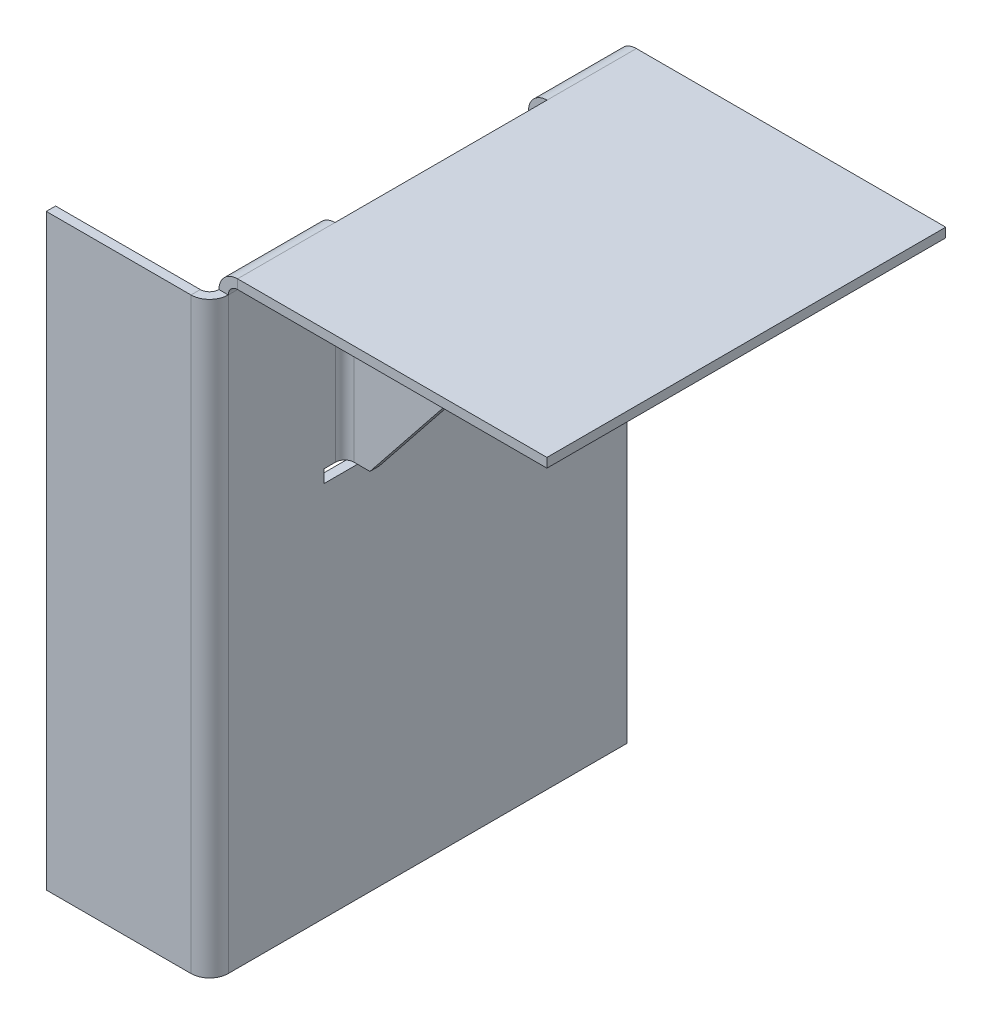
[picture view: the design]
ISO-10303-21;
HEADER;
FILE_DESCRIPTION(('STEP AP214'),'2;1');
FILE_NAME('part.step','',(''),(''),'','','');
FILE_SCHEMA(('AUTOMOTIVE_DESIGN { 1 0 10303 214 1 1 1 1 }'));
ENDSEC;
DATA;
#1=APPLICATION_CONTEXT('core data for automotive mechanical design processes');
#2=APPLICATION_PROTOCOL_DEFINITION('international standard','automotive_design',2000,#1);
#3=PRODUCT_CONTEXT('',#1,'mechanical');
#4=PRODUCT('Part','Part','',(#3));
#5=PRODUCT_RELATED_PRODUCT_CATEGORY('part','',(#4));
#6=PRODUCT_DEFINITION_FORMATION('','',#4);
#7=PRODUCT_DEFINITION_CONTEXT('part definition',#1,'design');
#8=PRODUCT_DEFINITION('design','',#6,#7);
#9=PRODUCT_DEFINITION_SHAPE('','',#8);
#10=(LENGTH_UNIT() NAMED_UNIT(*) SI_UNIT(.MILLI.,.METRE.));
#11=(NAMED_UNIT(*) PLANE_ANGLE_UNIT() SI_UNIT($,.RADIAN.));
#12=(NAMED_UNIT(*) SI_UNIT($,.STERADIAN.) SOLID_ANGLE_UNIT());
#13=UNCERTAINTY_MEASURE_WITH_UNIT(LENGTH_MEASURE(1.E-05),#10,'distance_accuracy_value','');
#14=(GEOMETRIC_REPRESENTATION_CONTEXT(3) GLOBAL_UNCERTAINTY_ASSIGNED_CONTEXT((#13)) GLOBAL_UNIT_ASSIGNED_CONTEXT((#10,
#11,#12)) REPRESENTATION_CONTEXT('',''));
#15=CARTESIAN_POINT('',(0.,0.,0.));
#16=DIRECTION('',(0.,0.,1.));
#17=DIRECTION('',(1.,0.,0.));
#18=AXIS2_PLACEMENT_3D('',#15,#16,#17);
#19=CARTESIAN_POINT('',(36.7177895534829,62.411644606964,-12.5039962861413));
#20=DIRECTION('',(0.,-1.,0.));
#21=DIRECTION('',(1.,0.,0.));
#22=AXIS2_PLACEMENT_3D('',#19,#20,#21);
#23=PLANE('',#22);
#24=DIRECTION('',(-1.,0.,0.));
#25=VECTOR('',#24,1.);
#26=CARTESIAN_POINT('',(36.717789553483,62.411644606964,-14.5039962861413));
#27=LINE('',#26,#25);
#28=CARTESIAN_POINT('',(36.717789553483,62.411644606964,-14.5039962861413));
#29=VERTEX_POINT('',#28);
#30=CARTESIAN_POINT('',(34.0135990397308,62.411644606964,-14.5039962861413));
#31=VERTEX_POINT('',#30);
#32=EDGE_CURVE('E74',#29,#31,#27,.T.);
#33=ORIENTED_EDGE('',*,*,#32,.T.);
#34=DIRECTION('',(0.,0.,-1.));
#35=VECTOR('',#34,1.);
#36=CARTESIAN_POINT('',(34.0135990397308,62.411644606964,-13.5039962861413));
#37=LINE('',#36,#35);
#38=CARTESIAN_POINT('',(34.0135990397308,62.411644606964,-13.5039962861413));
#39=VERTEX_POINT('',#38);
#40=EDGE_CURVE('E78',#39,#31,#37,.T.);
#41=ORIENTED_EDGE('',*,*,#40,.F.);
#42=DIRECTION('',(1.,0.,0.));
#43=VECTOR('',#42,1.);
#44=CARTESIAN_POINT('',(3.67105116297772,62.411644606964,-13.5039962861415));
#45=LINE('',#44,#43);
#46=CARTESIAN_POINT('',(36.717789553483,62.411644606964,-13.5039962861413));
#47=VERTEX_POINT('',#46);
#48=EDGE_CURVE('E305',#39,#47,#45,.T.);
#49=ORIENTED_EDGE('',*,*,#48,.T.);
#50=DIRECTION('',(0.,0.,-1.));
#51=VECTOR('',#50,1.);
#52=CARTESIAN_POINT('',(36.7177895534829,62.411644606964,-12.5039962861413));
#53=LINE('',#52,#51);
#54=EDGE_CURVE('E301',#47,#29,#53,.T.);
#55=ORIENTED_EDGE('',*,*,#54,.T.);
#56=EDGE_LOOP('',(#33,#41,#49,#55));
#57=FACE_BOUND('',#56,.T.);
#58=ADVANCED_FACE('F57',(#57),#23,.F.);
#59=CARTESIAN_POINT('',(18.5312419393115,41.7710744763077,-16.5624605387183));
#60=DIRECTION('',(0.,1.,0.));
#61=DIRECTION('',(0.,0.,1.));
#62=AXIS2_PLACEMENT_3D('',#59,#60,#61);
#63=PLANE('',#62);
#64=DIRECTION('',(0.,0.,-1.));
#65=VECTOR('',#64,1.);
#66=CARTESIAN_POINT('',(16.5312419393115,41.7710744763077,-16.5624605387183));
#67=LINE('',#66,#65);
#68=CARTESIAN_POINT('',(16.5312419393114,41.7710744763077,-11.2878468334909));
#69=VERTEX_POINT('',#68);
#70=CARTESIAN_POINT('',(16.5312419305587,41.7710744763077,-12.5039962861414));
#71=VERTEX_POINT('',#70);
#72=EDGE_CURVE('E61',#69,#71,#67,.T.);
#73=ORIENTED_EDGE('',*,*,#72,.T.);
#74=DIRECTION('',(1.,0.,0.));
#75=VECTOR('',#74,1.);
#76=CARTESIAN_POINT('',(18.5312419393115,41.7710744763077,-12.5039962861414));
#77=LINE('',#76,#75);
#78=CARTESIAN_POINT('',(17.5312419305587,41.7710744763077,-12.5039962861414));
#79=VERTEX_POINT('',#78);
#80=EDGE_CURVE('E524',#71,#79,#77,.T.);
#81=ORIENTED_EDGE('',*,*,#80,.T.);
#82=DIRECTION('',(0.,0.,1.));
#83=VECTOR('',#82,1.);
#84=CARTESIAN_POINT('',(17.5312419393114,41.7710744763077,0.));
#85=LINE('',#84,#83);
#86=CARTESIAN_POINT('',(17.5312419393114,41.7710744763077,-11.2878468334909));
#87=VERTEX_POINT('',#86);
#88=EDGE_CURVE('E387',#79,#87,#85,.T.);
#89=ORIENTED_EDGE('',*,*,#88,.T.);
#90=DIRECTION('',(-1.,0.,0.));
#91=VECTOR('',#90,1.);
#92=CARTESIAN_POINT('',(18.5312419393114,41.7710744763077,-11.2878468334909));
#93=LINE('',#92,#91);
#94=EDGE_CURVE('E362',#87,#69,#93,.T.);
#95=ORIENTED_EDGE('',*,*,#94,.T.);
#96=EDGE_LOOP('',(#73,#81,#89,#95));
#97=FACE_BOUND('',#96,.T.);
#98=ADVANCED_FACE('F535',(#97),#63,.F.);
#99=CARTESIAN_POINT('',(18.5312419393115,62.411644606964,-33.0467383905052));
#100=DIRECTION('',(0.,-1.,0.));
#101=DIRECTION('',(0.,0.,-1.));
#102=AXIS2_PLACEMENT_3D('',#99,#100,#101);
#103=PLANE('',#102);
#104=DIRECTION('',(0.,0.,-1.));
#105=VECTOR('',#104,1.);
#106=CARTESIAN_POINT('',(17.5312419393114,62.411644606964,0.));
#107=LINE('',#106,#105);
#108=CARTESIAN_POINT('',(17.5312419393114,62.411644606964,-11.4539814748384));
#109=VERTEX_POINT('',#108);
#110=CARTESIAN_POINT('',(17.5312419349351,62.411644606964,-12.5039962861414));
#111=VERTEX_POINT('',#110);
#112=EDGE_CURVE('E425',#109,#111,#107,.T.);
#113=ORIENTED_EDGE('',*,*,#112,.T.);
#114=DIRECTION('',(-1.,0.,0.));
#115=VECTOR('',#114,1.);
#116=CARTESIAN_POINT('',(18.5312419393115,62.411644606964,-12.5039962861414));
#117=LINE('',#116,#115);
#118=CARTESIAN_POINT('',(16.5312419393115,62.411644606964,-12.5039962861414));
#119=VERTEX_POINT('',#118);
#120=EDGE_CURVE('E13',#111,#119,#117,.T.);
#121=ORIENTED_EDGE('',*,*,#120,.T.);
#122=DIRECTION('',(0.,0.,1.));
#123=VECTOR('',#122,1.);
#124=CARTESIAN_POINT('',(16.5312419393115,62.411644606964,-33.0467383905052));
#125=LINE('',#124,#123);
#126=CARTESIAN_POINT('',(16.5312419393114,62.411644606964,-11.4539814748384));
#127=VERTEX_POINT('',#126);
#128=EDGE_CURVE('E336',#119,#127,#125,.T.);
#129=ORIENTED_EDGE('',*,*,#128,.T.);
#130=DIRECTION('',(-1.,0.,0.));
#131=VECTOR('',#130,1.);
#132=CARTESIAN_POINT('',(18.5312419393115,62.411644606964,-11.4539814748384));
#133=LINE('',#132,#131);
#134=EDGE_CURVE('E347',#109,#127,#133,.T.);
#135=ORIENTED_EDGE('',*,*,#134,.F.);
#136=EDGE_LOOP('',(#113,#121,#129,#135));
#137=FACE_BOUND('',#136,.T.);
#138=ADVANCED_FACE('F59',(#137),#103,.F.);
#139=CARTESIAN_POINT('',(16.5312419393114,0.,0.));
#140=DIRECTION('',(1.,0.,0.));
#141=DIRECTION('',(0.,0.,-1.));
#142=AXIS2_PLACEMENT_3D('',#139,#140,#141);
#143=PLANE('',#142);
#144=ORIENTED_EDGE('',*,*,#128,.F.);
#145=DIRECTION('',(0.,-1.,0.));
#146=VECTOR('',#145,1.);
#147=CARTESIAN_POINT('',(16.5312419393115,0.,-12.5039962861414));
#148=LINE('',#147,#146);
#149=EDGE_CURVE('E66',#119,#71,#148,.T.);
#150=ORIENTED_EDGE('',*,*,#149,.T.);
#151=ORIENTED_EDGE('',*,*,#72,.F.);
#152=DIRECTION('',(0.,1.,0.));
#153=VECTOR('',#152,1.);
#154=CARTESIAN_POINT('',(16.5312419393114,41.7710744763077,-11.2878468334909));
#155=LINE('',#154,#153);
#156=CARTESIAN_POINT('',(16.5312419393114,40.4026864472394,-11.2878468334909));
#157=VERTEX_POINT('',#156);
#158=EDGE_CURVE('E359',#157,#69,#155,.T.);
#159=ORIENTED_EDGE('',*,*,#158,.F.);
#160=DIRECTION('',(0.,0.,1.));
#161=VECTOR('',#160,1.);
#162=CARTESIAN_POINT('',(16.5312419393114,40.4026864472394,-11.2878468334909));
#163=LINE('',#162,#161);
#164=CARTESIAN_POINT('',(16.5312419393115,40.4026864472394,-16.9317383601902));
#165=VERTEX_POINT('',#164);
#166=EDGE_CURVE('E356',#165,#157,#163,.T.);
#167=ORIENTED_EDGE('',*,*,#166,.F.);
#168=DIRECTION('',(0.,-0.781388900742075,0.62404437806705));
#169=VECTOR('',#168,1.);
#170=CARTESIAN_POINT('',(16.5312419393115,40.4026864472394,-16.9317383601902));
#171=LINE('',#170,#169);
#172=CARTESIAN_POINT('',(16.5312419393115,62.0423667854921,-34.2139404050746));
#173=VERTEX_POINT('',#172);
#174=EDGE_CURVE('E353',#173,#165,#171,.T.);
#175=ORIENTED_EDGE('',*,*,#174,.F.);
#176=DIRECTION('',(0.,-1.,0.));
#177=VECTOR('',#176,1.);
#178=CARTESIAN_POINT('',(16.5312419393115,62.0423667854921,-34.2139404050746));
#179=LINE('',#178,#177);
#180=CARTESIAN_POINT('',(16.5312419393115,63.0741376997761,-34.2139404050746));
#181=VERTEX_POINT('',#180);
#182=EDGE_CURVE('E350',#181,#173,#179,.T.);
#183=ORIENTED_EDGE('',*,*,#182,.F.);
#184=DIRECTION('',(0.,0.,-1.));
#185=VECTOR('',#184,1.);
#186=CARTESIAN_POINT('',(16.5312419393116,63.0741376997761,-43.8));
#187=LINE('',#186,#185);
#188=CARTESIAN_POINT('',(16.5312419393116,63.0741376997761,-43.8));
#189=VERTEX_POINT('',#188);
#190=EDGE_CURVE('E447',#181,#189,#187,.T.);
#191=ORIENTED_EDGE('',*,*,#190,.T.);
#192=DIRECTION('',(0.,-1.,0.));
#193=VECTOR('',#192,1.);
#194=CARTESIAN_POINT('',(16.5312419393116,0.,-43.8));
#195=LINE('',#194,#193);
#196=CARTESIAN_POINT('',(16.5312419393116,0.,-43.8));
#197=VERTEX_POINT('',#196);
#198=EDGE_CURVE('E462',#189,#197,#195,.T.);
#199=ORIENTED_EDGE('',*,*,#198,.T.);
#200=DIRECTION('',(0.,0.,1.));
#201=VECTOR('',#200,1.);
#202=CARTESIAN_POINT('',(16.5312419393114,0.,0.));
#203=LINE('',#202,#201);
#204=CARTESIAN_POINT('',(16.5312419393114,0.,-0.999999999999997));
#205=VERTEX_POINT('',#204);
#206=EDGE_CURVE('E465',#197,#205,#203,.T.);
#207=ORIENTED_EDGE('',*,*,#206,.T.);
#208=DIRECTION('',(0.,-1.,0.));
#209=VECTOR('',#208,1.);
#210=CARTESIAN_POINT('',(16.5312419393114,63.0741376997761,-0.999999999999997));
#211=LINE('',#210,#209);
#212=CARTESIAN_POINT('',(16.5312419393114,63.0741376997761,-0.999999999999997));
#213=VERTEX_POINT('',#212);
#214=EDGE_CURVE('E438',#213,#205,#211,.T.);
#215=ORIENTED_EDGE('',*,*,#214,.F.);
#216=CARTESIAN_POINT('',(16.5312419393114,63.0741376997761,-11.4539814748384));
#217=VERTEX_POINT('',#216);
#218=EDGE_CURVE('E459',#213,#217,#187,.T.);
#219=ORIENTED_EDGE('',*,*,#218,.T.);
#220=DIRECTION('',(0.,1.,0.));
#221=VECTOR('',#220,1.);
#222=CARTESIAN_POINT('',(16.5312419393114,62.411644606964,-11.4539814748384));
#223=LINE('',#222,#221);
#224=EDGE_CURVE('E348',#127,#217,#223,.T.);
#225=ORIENTED_EDGE('',*,*,#224,.F.);
#226=EDGE_LOOP('',(#144,#150,#151,#159,#167,#175,#183,#191,#199,#207,#215,#219,#225));
#227=FACE_BOUND('',#226,.T.);
#228=ADVANCED_FACE('F559',(#227),#143,.F.);
#229=CARTESIAN_POINT('',(18.5312419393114,63.0741376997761,-0.99999999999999));
#230=DIRECTION('',(0.,0.,1.));
#231=DIRECTION('',(0.,1.,0.));
#232=AXIS2_PLACEMENT_3D('',#229,#230,#231);
#233=CYLINDRICAL_SURFACE('',#232,2.);
#234=CARTESIAN_POINT('',(18.5312419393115,63.0741376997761,-34.2139404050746));
#235=DIRECTION('',(0.,0.,-1.));
#236=DIRECTION('',(-1.,0.,0.));
#237=AXIS2_PLACEMENT_3D('',#234,#235,#236);
#238=CIRCLE('',#237,2.);
#239=CARTESIAN_POINT('',(18.5312419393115,65.0741376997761,-34.2139404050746));
#240=VERTEX_POINT('',#239);
#241=EDGE_CURVE('E379',#240,#181,#238,.F.);
#242=ORIENTED_EDGE('',*,*,#241,.F.);
#243=DIRECTION('',(0.,0.,1.));
#244=VECTOR('',#243,1.);
#245=CARTESIAN_POINT('',(18.5312419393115,65.0741376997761,-43.7999999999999));
#246=LINE('',#245,#244);
#247=CARTESIAN_POINT('',(18.5312419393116,65.0741376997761,-43.8));
#248=VERTEX_POINT('',#247);
#249=EDGE_CURVE('E413',#240,#248,#246,.F.);
#250=ORIENTED_EDGE('',*,*,#249,.T.);
#251=CARTESIAN_POINT('',(18.5312419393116,63.0741376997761,-43.8));
#252=DIRECTION('',(0.,0.,1.));
#253=DIRECTION('',(1.,0.,0.));
#254=AXIS2_PLACEMENT_3D('',#251,#252,#253);
#255=CIRCLE('',#254,2.);
#256=EDGE_CURVE('E426',#189,#248,#255,.F.);
#257=ORIENTED_EDGE('',*,*,#256,.F.);
#258=ORIENTED_EDGE('',*,*,#190,.F.);
#259=EDGE_LOOP('',(#242,#250,#257,#258));
#260=FACE_BOUND('',#259,.T.);
#261=ADVANCED_FACE('F807',(#260),#233,.T.);
#262=CARTESIAN_POINT('',(18.5312419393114,63.0741376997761,-0.99999999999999));
#263=DIRECTION('',(0.,0.,1.));
#264=DIRECTION('',(0.,1.,0.));
#265=AXIS2_PLACEMENT_3D('',#262,#263,#264);
#266=CYLINDRICAL_SURFACE('',#265,1.);
#267=DIRECTION('',(0.,0.,1.));
#268=VECTOR('',#267,1.);
#269=CARTESIAN_POINT('',(18.5312419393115,64.0741376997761,-43.7999999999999));
#270=LINE('',#269,#268);
#271=CARTESIAN_POINT('',(18.5312419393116,64.0741376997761,-43.8));
#272=VERTEX_POINT('',#271);
#273=CARTESIAN_POINT('',(18.5312419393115,64.0741376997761,-34.2139404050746));
#274=VERTEX_POINT('',#273);
#275=EDGE_CURVE('E417',#272,#274,#270,.T.);
#276=ORIENTED_EDGE('',*,*,#275,.T.);
#277=CARTESIAN_POINT('',(18.5312419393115,63.0741376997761,-34.2139404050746));
#278=DIRECTION('',(0.,0.,-1.));
#279=DIRECTION('',(-1.,0.,0.));
#280=AXIS2_PLACEMENT_3D('',#277,#278,#279);
#281=CIRCLE('',#280,1.);
#282=CARTESIAN_POINT('',(17.5312419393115,63.0741376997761,-34.2139404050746));
#283=VERTEX_POINT('',#282);
#284=EDGE_CURVE('E519',#274,#283,#281,.F.);
#285=ORIENTED_EDGE('',*,*,#284,.T.);
#286=DIRECTION('',(0.,0.,-1.));
#287=VECTOR('',#286,1.);
#288=CARTESIAN_POINT('',(17.5312419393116,63.0741376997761,-43.8));
#289=LINE('',#288,#287);
#290=CARTESIAN_POINT('',(17.5312419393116,63.0741376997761,-43.8));
#291=VERTEX_POINT('',#290);
#292=EDGE_CURVE('E452',#283,#291,#289,.T.);
#293=ORIENTED_EDGE('',*,*,#292,.T.);
#294=CARTESIAN_POINT('',(18.5312419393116,63.0741376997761,-43.8));
#295=DIRECTION('',(0.,0.,1.));
#296=DIRECTION('',(1.,0.,0.));
#297=AXIS2_PLACEMENT_3D('',#294,#295,#296);
#298=CIRCLE('',#297,1.);
#299=EDGE_CURVE('E433',#291,#272,#298,.F.);
#300=ORIENTED_EDGE('',*,*,#299,.T.);
#301=EDGE_LOOP('',(#276,#285,#293,#300));
#302=FACE_BOUND('',#301,.T.);
#303=ADVANCED_FACE('F865',(#302),#266,.F.);
#304=CARTESIAN_POINT('',(0.,0.,1.));
#305=DIRECTION('',(0.,1.,0.));
#306=DIRECTION('',(0.,0.,1.));
#307=AXIS2_PLACEMENT_3D('',#304,#305,#306);
#308=PLANE('',#307);
#309=DIRECTION('',(0.,0.,1.));
#310=VECTOR('',#309,1.);
#311=CARTESIAN_POINT('',(15.5312419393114,0.,0.));
#312=LINE('',#311,#310);
#313=CARTESIAN_POINT('',(15.5312419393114,0.,0.));
#314=VERTEX_POINT('',#313);
#315=CARTESIAN_POINT('',(15.5312419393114,0.,1.));
#316=VERTEX_POINT('',#315);
#317=EDGE_CURVE('E479',#314,#316,#312,.T.);
#318=ORIENTED_EDGE('',*,*,#317,.T.);
#319=DIRECTION('',(1.,0.,0.));
#320=VECTOR('',#319,1.);
#321=CARTESIAN_POINT('',(0.,0.,1.));
#322=LINE('',#321,#320);
#323=CARTESIAN_POINT('',(0.,0.,1.));
#324=VERTEX_POINT('',#323);
#325=EDGE_CURVE('E499',#324,#316,#322,.T.);
#326=ORIENTED_EDGE('',*,*,#325,.F.);
#327=DIRECTION('',(0.,0.,-1.));
#328=VECTOR('',#327,1.);
#329=CARTESIAN_POINT('',(0.,0.,1.));
#330=LINE('',#329,#328);
#331=CARTESIAN_POINT('',(0.,0.,0.));
#332=VERTEX_POINT('',#331);
#333=EDGE_CURVE('E513',#324,#332,#330,.T.);
#334=ORIENTED_EDGE('',*,*,#333,.T.);
#335=DIRECTION('',(1.,0.,0.));
#336=VECTOR('',#335,1.);
#337=CARTESIAN_POINT('',(0.,0.,0.));
#338=LINE('',#337,#336);
#339=EDGE_CURVE('E507',#332,#314,#338,.T.);
#340=ORIENTED_EDGE('',*,*,#339,.T.);
#341=EDGE_LOOP('',(#318,#326,#334,#340));
#342=FACE_BOUND('',#341,.T.);
#343=ADVANCED_FACE('F605',(#342),#308,.F.);
#344=CARTESIAN_POINT('',(0.,63.0741376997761,1.));
#345=DIRECTION('',(0.,-1.,0.));
#346=DIRECTION('',(0.,0.,-1.));
#347=AXIS2_PLACEMENT_3D('',#344,#345,#346);
#348=PLANE('',#347);
#349=DIRECTION('',(0.,0.,1.));
#350=VECTOR('',#349,1.);
#351=CARTESIAN_POINT('',(15.5312419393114,63.0741376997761,0.));
#352=LINE('',#351,#350);
#353=CARTESIAN_POINT('',(15.5312419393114,63.0741376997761,0.));
#354=VERTEX_POINT('',#353);
#355=CARTESIAN_POINT('',(15.5312419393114,63.0741376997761,1.));
#356=VERTEX_POINT('',#355);
#357=EDGE_CURVE('E490',#354,#356,#352,.T.);
#358=ORIENTED_EDGE('',*,*,#357,.F.);
#359=DIRECTION('',(-1.,0.,0.));
#360=VECTOR('',#359,1.);
#361=CARTESIAN_POINT('',(0.,63.0741376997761,0.));
#362=LINE('',#361,#360);
#363=CARTESIAN_POINT('',(0.,63.0741376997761,0.));
#364=VERTEX_POINT('',#363);
#365=EDGE_CURVE('E500',#354,#364,#362,.T.);
#366=ORIENTED_EDGE('',*,*,#365,.T.);
#367=DIRECTION('',(0.,0.,-1.));
#368=VECTOR('',#367,1.);
#369=CARTESIAN_POINT('',(0.,63.0741376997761,1.));
#370=LINE('',#369,#368);
#371=CARTESIAN_POINT('',(0.,63.0741376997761,1.));
#372=VERTEX_POINT('',#371);
#373=EDGE_CURVE('E504',#372,#364,#370,.T.);
#374=ORIENTED_EDGE('',*,*,#373,.F.);
#375=DIRECTION('',(-1.,0.,0.));
#376=VECTOR('',#375,1.);
#377=CARTESIAN_POINT('',(0.,63.0741376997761,1.));
#378=LINE('',#377,#376);
#379=EDGE_CURVE('E502',#356,#372,#378,.T.);
#380=ORIENTED_EDGE('',*,*,#379,.F.);
#381=EDGE_LOOP('',(#358,#366,#374,#380));
#382=FACE_BOUND('',#381,.T.);
#383=ADVANCED_FACE('F619',(#382),#348,.F.);
#384=CARTESIAN_POINT('',(0.,63.0741376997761,1.));
#385=DIRECTION('',(0.,0.,-1.));
#386=DIRECTION('',(-1.,0.,0.));
#387=AXIS2_PLACEMENT_3D('',#384,#385,#386);
#388=PLANE('',#387);
#389=DIRECTION('',(0.,-1.,0.));
#390=VECTOR('',#389,1.);
#391=CARTESIAN_POINT('',(15.5312419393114,0.,1.));
#392=LINE('',#391,#390);
#393=EDGE_CURVE('E473',#316,#356,#392,.F.);
#394=ORIENTED_EDGE('',*,*,#393,.T.);
#395=ORIENTED_EDGE('',*,*,#379,.T.);
#396=DIRECTION('',(0.,-1.,0.));
#397=VECTOR('',#396,1.);
#398=CARTESIAN_POINT('',(0.,0.,1.));
#399=LINE('',#398,#397);
#400=EDGE_CURVE('E496',#372,#324,#399,.T.);
#401=ORIENTED_EDGE('',*,*,#400,.T.);
#402=ORIENTED_EDGE('',*,*,#325,.T.);
#403=EDGE_LOOP('',(#394,#395,#401,#402));
#404=FACE_BOUND('',#403,.T.);
#405=ADVANCED_FACE('F616',(#404),#388,.F.);
#406=CARTESIAN_POINT('',(0.,63.0741376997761,0.));
#407=DIRECTION('',(0.,0.,-1.));
#408=DIRECTION('',(-1.,0.,0.));
#409=AXIS2_PLACEMENT_3D('',#406,#407,#408);
#410=PLANE('',#409);
#411=ORIENTED_EDGE('',*,*,#365,.F.);
#412=DIRECTION('',(0.,-1.,0.));
#413=VECTOR('',#412,1.);
#414=CARTESIAN_POINT('',(15.5312419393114,0.,0.));
#415=LINE('',#414,#413);
#416=EDGE_CURVE('E485',#314,#354,#415,.F.);
#417=ORIENTED_EDGE('',*,*,#416,.F.);
#418=ORIENTED_EDGE('',*,*,#339,.F.);
#419=DIRECTION('',(0.,-1.,0.));
#420=VECTOR('',#419,1.);
#421=CARTESIAN_POINT('',(0.,0.,0.));
#422=LINE('',#421,#420);
#423=EDGE_CURVE('E493',#364,#332,#422,.T.);
#424=ORIENTED_EDGE('',*,*,#423,.F.);
#425=EDGE_LOOP('',(#411,#417,#418,#424));
#426=FACE_BOUND('',#425,.T.);
#427=ADVANCED_FACE('F601',(#426),#410,.T.);
#428=CARTESIAN_POINT('',(0.,0.,1.));
#429=DIRECTION('',(1.,0.,0.));
#430=DIRECTION('',(0.,0.,-1.));
#431=AXIS2_PLACEMENT_3D('',#428,#429,#430);
#432=PLANE('',#431);
#433=ORIENTED_EDGE('',*,*,#423,.T.);
#434=ORIENTED_EDGE('',*,*,#333,.F.);
#435=ORIENTED_EDGE('',*,*,#400,.F.);
#436=ORIENTED_EDGE('',*,*,#373,.T.);
#437=EDGE_LOOP('',(#433,#434,#435,#436));
#438=FACE_BOUND('',#437,.T.);
#439=ADVANCED_FACE('F622',(#438),#432,.F.);
#440=CARTESIAN_POINT('',(15.5312419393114,63.0741376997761,-1.));
#441=DIRECTION('',(0.,1.,0.));
#442=DIRECTION('',(0.,0.,1.));
#443=AXIS2_PLACEMENT_3D('',#440,#441,#442);
#444=PLANE('',#443);
#445=DIRECTION('',(1.,0.,0.));
#446=VECTOR('',#445,1.);
#447=CARTESIAN_POINT('',(16.5312419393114,63.0741376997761,-0.999999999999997));
#448=LINE('',#447,#446);
#449=CARTESIAN_POINT('',(17.5312419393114,63.0741376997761,-0.999999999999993));
#450=VERTEX_POINT('',#449);
#451=EDGE_CURVE('E429',#213,#450,#448,.T.);
#452=ORIENTED_EDGE('',*,*,#451,.F.);
#453=CARTESIAN_POINT('',(15.5312419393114,63.0741376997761,-1.));
#454=DIRECTION('',(0.,-1.,0.));
#455=DIRECTION('',(0.,0.,-1.));
#456=AXIS2_PLACEMENT_3D('',#453,#454,#455);
#457=CIRCLE('',#456,1.);
#458=EDGE_CURVE('E482',#354,#213,#457,.F.);
#459=ORIENTED_EDGE('',*,*,#458,.F.);
#460=ORIENTED_EDGE('',*,*,#357,.T.);
#461=CARTESIAN_POINT('',(15.5312419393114,63.0741376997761,-1.));
#462=DIRECTION('',(0.,-1.,0.));
#463=DIRECTION('',(0.,0.,-1.));
#464=AXIS2_PLACEMENT_3D('',#461,#462,#463);
#465=CIRCLE('',#464,2.);
#466=EDGE_CURVE('E475',#356,#450,#465,.F.);
#467=ORIENTED_EDGE('',*,*,#466,.T.);
#468=EDGE_LOOP('',(#452,#459,#460,#467));
#469=FACE_BOUND('',#468,.T.);
#470=ADVANCED_FACE('F593',(#469),#444,.T.);
#471=CARTESIAN_POINT('',(15.5312419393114,0.,-1.));
#472=DIRECTION('',(0.,1.,0.));
#473=DIRECTION('',(0.,0.,1.));
#474=AXIS2_PLACEMENT_3D('',#471,#472,#473);
#475=PLANE('',#474);
#476=CARTESIAN_POINT('',(15.5312419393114,0.,-1.));
#477=DIRECTION('',(0.,-1.,0.));
#478=DIRECTION('',(0.,0.,-1.));
#479=AXIS2_PLACEMENT_3D('',#476,#477,#478);
#480=CIRCLE('',#479,1.);
#481=EDGE_CURVE('E470',#205,#314,#480,.T.);
#482=ORIENTED_EDGE('',*,*,#481,.F.);
#483=DIRECTION('',(1.,0.,0.));
#484=VECTOR('',#483,1.);
#485=CARTESIAN_POINT('',(16.5312419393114,0.,-0.999999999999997));
#486=LINE('',#485,#484);
#487=CARTESIAN_POINT('',(17.5312419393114,0.,-0.999999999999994));
#488=VERTEX_POINT('',#487);
#489=EDGE_CURVE('E440',#205,#488,#486,.T.);
#490=ORIENTED_EDGE('',*,*,#489,.T.);
#491=CARTESIAN_POINT('',(15.5312419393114,0.,-1.));
#492=DIRECTION('',(0.,-1.,0.));
#493=DIRECTION('',(0.,0.,-1.));
#494=AXIS2_PLACEMENT_3D('',#491,#492,#493);
#495=CIRCLE('',#494,2.);
#496=EDGE_CURVE('E476',#488,#316,#495,.T.);
#497=ORIENTED_EDGE('',*,*,#496,.T.);
#498=ORIENTED_EDGE('',*,*,#317,.F.);
#499=EDGE_LOOP('',(#482,#490,#497,#498));
#500=FACE_BOUND('',#499,.T.);
#501=ADVANCED_FACE('F609',(#500),#475,.F.);
#502=CARTESIAN_POINT('',(15.5312419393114,0.,-1.));
#503=DIRECTION('',(0.,-1.,0.));
#504=DIRECTION('',(1.,0.,0.));
#505=AXIS2_PLACEMENT_3D('',#502,#503,#504);
#506=CYLINDRICAL_SURFACE('',#505,2.);
#507=ORIENTED_EDGE('',*,*,#393,.F.);
#508=ORIENTED_EDGE('',*,*,#496,.F.);
#509=DIRECTION('',(0.,-1.,0.));
#510=VECTOR('',#509,1.);
#511=CARTESIAN_POINT('',(17.5312419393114,0.,-0.999999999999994));
#512=LINE('',#511,#510);
#513=EDGE_CURVE('E443',#450,#488,#512,.T.);
#514=ORIENTED_EDGE('',*,*,#513,.F.);
#515=ORIENTED_EDGE('',*,*,#466,.F.);
#516=EDGE_LOOP('',(#507,#508,#514,#515));
#517=FACE_BOUND('',#516,.T.);
#518=ADVANCED_FACE('F613',(#517),#506,.T.);
#519=CARTESIAN_POINT('',(15.5312419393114,0.,-1.));
#520=DIRECTION('',(0.,-1.,0.));
#521=DIRECTION('',(1.,0.,0.));
#522=AXIS2_PLACEMENT_3D('',#519,#520,#521);
#523=CYLINDRICAL_SURFACE('',#522,1.);
#524=ORIENTED_EDGE('',*,*,#416,.T.);
#525=ORIENTED_EDGE('',*,*,#458,.T.);
#526=ORIENTED_EDGE('',*,*,#214,.T.);
#527=ORIENTED_EDGE('',*,*,#481,.T.);
#528=EDGE_LOOP('',(#524,#525,#526,#527));
#529=FACE_BOUND('',#528,.T.);
#530=ADVANCED_FACE('F597',(#529),#523,.F.);
#531=CARTESIAN_POINT('',(17.5312419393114,0.,0.));
#532=DIRECTION('',(0.,-1.,0.));
#533=DIRECTION('',(0.,0.,-1.));
#534=AXIS2_PLACEMENT_3D('',#531,#532,#533);
#535=PLANE('',#534);
#536=DIRECTION('',(0.,0.,1.));
#537=VECTOR('',#536,1.);
#538=CARTESIAN_POINT('',(17.5312419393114,0.,0.));
#539=LINE('',#538,#537);
#540=CARTESIAN_POINT('',(17.5312419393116,0.,-43.8));
#541=VERTEX_POINT('',#540);
#542=EDGE_CURVE('E455',#541,#488,#539,.T.);
#543=ORIENTED_EDGE('',*,*,#542,.T.);
#544=ORIENTED_EDGE('',*,*,#489,.F.);
#545=ORIENTED_EDGE('',*,*,#206,.F.);
#546=DIRECTION('',(-1.,0.,0.));
#547=VECTOR('',#546,1.);
#548=CARTESIAN_POINT('',(17.5312419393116,0.,-43.8));
#549=LINE('',#548,#547);
#550=EDGE_CURVE('E468',#541,#197,#549,.T.);
#551=ORIENTED_EDGE('',*,*,#550,.F.);
#552=EDGE_LOOP('',(#543,#544,#545,#551));
#553=FACE_BOUND('',#552,.T.);
#554=ADVANCED_FACE('F978',(#553),#535,.T.);
#555=CARTESIAN_POINT('',(17.5312419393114,0.,0.));
#556=DIRECTION('',(1.,0.,0.));
#557=DIRECTION('',(0.,0.,-1.));
#558=AXIS2_PLACEMENT_3D('',#555,#556,#557);
#559=PLANE('',#558);
#560=DIRECTION('',(0.,-1.,0.));
#561=VECTOR('',#560,1.);
#562=CARTESIAN_POINT('',(17.5312419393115,0.,-12.5039962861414));
#563=LINE('',#562,#561);
#564=EDGE_CURVE('E522',#111,#79,#563,.T.);
#565=ORIENTED_EDGE('',*,*,#564,.F.);
#566=ORIENTED_EDGE('',*,*,#112,.F.);
#567=DIRECTION('',(0.,-1.,0.));
#568=VECTOR('',#567,1.);
#569=CARTESIAN_POINT('',(17.5312419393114,0.,-11.4539814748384));
#570=LINE('',#569,#568);
#571=CARTESIAN_POINT('',(17.5312419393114,63.0741376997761,-11.4539814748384));
#572=VERTEX_POINT('',#571);
#573=EDGE_CURVE('E364',#572,#109,#570,.T.);
#574=ORIENTED_EDGE('',*,*,#573,.F.);
#575=EDGE_CURVE('E448',#450,#572,#289,.T.);
#576=ORIENTED_EDGE('',*,*,#575,.F.);
#577=ORIENTED_EDGE('',*,*,#513,.T.);
#578=ORIENTED_EDGE('',*,*,#542,.F.);
#579=DIRECTION('',(0.,-1.,0.));
#580=VECTOR('',#579,1.);
#581=CARTESIAN_POINT('',(17.5312419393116,0.,-43.8));
#582=LINE('',#581,#580);
#583=EDGE_CURVE('E451',#291,#541,#582,.T.);
#584=ORIENTED_EDGE('',*,*,#583,.F.);
#585=ORIENTED_EDGE('',*,*,#292,.F.);
#586=DIRECTION('',(0.,1.,0.));
#587=VECTOR('',#586,1.);
#588=CARTESIAN_POINT('',(17.5312419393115,0.,-34.2139404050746));
#589=LINE('',#588,#587);
#590=CARTESIAN_POINT('',(17.5312419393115,62.0423667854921,-34.2139404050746));
#591=VERTEX_POINT('',#590);
#592=EDGE_CURVE('E377',#591,#283,#589,.T.);
#593=ORIENTED_EDGE('',*,*,#592,.F.);
#594=DIRECTION('',(0.,0.781388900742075,-0.62404437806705));
#595=VECTOR('',#594,1.);
#596=CARTESIAN_POINT('',(17.5312419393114,7.47779704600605,9.36322450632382));
#597=LINE('',#596,#595);
#598=CARTESIAN_POINT('',(17.5312419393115,40.4026864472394,-16.9317383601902));
#599=VERTEX_POINT('',#598);
#600=EDGE_CURVE('E381',#599,#591,#597,.T.);
#601=ORIENTED_EDGE('',*,*,#600,.F.);
#602=DIRECTION('',(0.,0.,-1.));
#603=VECTOR('',#602,1.);
#604=CARTESIAN_POINT('',(17.5312419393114,40.4026864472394,0.));
#605=LINE('',#604,#603);
#606=CARTESIAN_POINT('',(17.5312419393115,40.4026864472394,-11.2878468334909));
#607=VERTEX_POINT('',#606);
#608=EDGE_CURVE('E383',#607,#599,#605,.T.);
#609=ORIENTED_EDGE('',*,*,#608,.F.);
#610=DIRECTION('',(0.,-1.,0.));
#611=VECTOR('',#610,1.);
#612=CARTESIAN_POINT('',(17.5312419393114,0.,-11.2878468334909));
#613=LINE('',#612,#611);
#614=EDGE_CURVE('E385',#87,#607,#613,.T.);
#615=ORIENTED_EDGE('',*,*,#614,.F.);
#616=ORIENTED_EDGE('',*,*,#88,.F.);
#617=EDGE_LOOP('',(#565,#566,#574,#576,#577,#578,#584,#585,#593,#601,#609,#615,#616));
#618=FACE_BOUND('',#617,.T.);
#619=ADVANCED_FACE('F545',(#618),#559,.T.);
#620=CARTESIAN_POINT('',(17.5312419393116,0.,-43.8));
#621=DIRECTION('',(0.,0.,-1.));
#622=DIRECTION('',(-1.,0.,0.));
#623=AXIS2_PLACEMENT_3D('',#620,#621,#622);
#624=PLANE('',#623);
#625=ORIENTED_EDGE('',*,*,#198,.F.);
#626=DIRECTION('',(-1.,0.,0.));
#627=VECTOR('',#626,1.);
#628=CARTESIAN_POINT('',(17.5312419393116,63.0741376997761,-43.8));
#629=LINE('',#628,#627);
#630=EDGE_CURVE('E458',#291,#189,#629,.T.);
#631=ORIENTED_EDGE('',*,*,#630,.F.);
#632=ORIENTED_EDGE('',*,*,#583,.T.);
#633=ORIENTED_EDGE('',*,*,#550,.T.);
#634=EDGE_LOOP('',(#625,#631,#632,#633));
#635=FACE_BOUND('',#634,.T.);
#636=ADVANCED_FACE('F959',(#635),#624,.T.);
#637=CARTESIAN_POINT('',(18.5312419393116,63.0741376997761,-43.8));
#638=DIRECTION('',(0.,0.,-1.));
#639=DIRECTION('',(-1.,0.,0.));
#640=AXIS2_PLACEMENT_3D('',#637,#638,#639);
#641=PLANE('',#640);
#642=DIRECTION('',(0.,1.,0.));
#643=VECTOR('',#642,1.);
#644=CARTESIAN_POINT('',(18.5312419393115,65.0741376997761,-43.8));
#645=LINE('',#644,#643);
#646=EDGE_CURVE('E422',#272,#248,#645,.T.);
#647=ORIENTED_EDGE('',*,*,#646,.F.);
#648=ORIENTED_EDGE('',*,*,#299,.F.);
#649=ORIENTED_EDGE('',*,*,#630,.T.);
#650=ORIENTED_EDGE('',*,*,#256,.T.);
#651=EDGE_LOOP('',(#647,#648,#649,#650));
#652=FACE_BOUND('',#651,.T.);
#653=ADVANCED_FACE('F944',(#652),#641,.T.);
#654=CARTESIAN_POINT('',(18.5312419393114,63.0741376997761,-0.99999999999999));
#655=DIRECTION('',(0.,0.,-1.));
#656=DIRECTION('',(-1.,0.,0.));
#657=AXIS2_PLACEMENT_3D('',#654,#655,#656);
#658=PLANE('',#657);
#659=CARTESIAN_POINT('',(18.5312419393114,63.0741376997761,-0.99999999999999));
#660=DIRECTION('',(0.,0.,1.));
#661=DIRECTION('',(1.,0.,0.));
#662=AXIS2_PLACEMENT_3D('',#659,#660,#661);
#663=CIRCLE('',#662,1.);
#664=CARTESIAN_POINT('',(18.5312419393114,64.0741376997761,-0.99999999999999));
#665=VERTEX_POINT('',#664);
#666=EDGE_CURVE('E390',#665,#450,#663,.T.);
#667=ORIENTED_EDGE('',*,*,#666,.F.);
#668=DIRECTION('',(0.,1.,0.));
#669=VECTOR('',#668,1.);
#670=CARTESIAN_POINT('',(18.5312419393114,64.0741376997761,-0.999999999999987));
#671=LINE('',#670,#669);
#672=CARTESIAN_POINT('',(18.5312419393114,65.0741376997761,-0.99999999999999));
#673=VERTEX_POINT('',#672);
#674=EDGE_CURVE('E414',#665,#673,#671,.T.);
#675=ORIENTED_EDGE('',*,*,#674,.T.);
#676=CARTESIAN_POINT('',(18.5312419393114,63.0741376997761,-0.99999999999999));
#677=DIRECTION('',(0.,0.,1.));
#678=DIRECTION('',(1.,0.,0.));
#679=AXIS2_PLACEMENT_3D('',#676,#677,#678);
#680=CIRCLE('',#679,2.);
#681=EDGE_CURVE('E430',#673,#213,#680,.T.);
#682=ORIENTED_EDGE('',*,*,#681,.T.);
#683=ORIENTED_EDGE('',*,*,#451,.T.);
#684=EDGE_LOOP('',(#667,#675,#682,#683));
#685=FACE_BOUND('',#684,.T.);
#686=ADVANCED_FACE('F588',(#685),#658,.F.);
#687=CARTESIAN_POINT('',(18.5312419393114,63.0741376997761,-11.4539814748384));
#688=DIRECTION('',(0.,0.,1.));
#689=DIRECTION('',(1.,0.,0.));
#690=AXIS2_PLACEMENT_3D('',#687,#688,#689);
#691=CIRCLE('',#690,2.);
#692=CARTESIAN_POINT('',(18.5312419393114,65.0741376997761,-11.4539814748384));
#693=VERTEX_POINT('',#692);
#694=EDGE_CURVE('E374',#217,#693,#691,.F.);
#695=ORIENTED_EDGE('',*,*,#694,.F.);
#696=ORIENTED_EDGE('',*,*,#218,.F.);
#697=ORIENTED_EDGE('',*,*,#681,.F.);
#698=EDGE_CURVE('E410',#673,#693,#246,.F.);
#699=ORIENTED_EDGE('',*,*,#698,.T.);
#700=EDGE_LOOP('',(#695,#696,#697,#699));
#701=FACE_BOUND('',#700,.T.);
#702=ADVANCED_FACE('F584',(#701),#233,.T.);
#703=ORIENTED_EDGE('',*,*,#575,.T.);
#704=CARTESIAN_POINT('',(18.5312419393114,63.0741376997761,-11.4539814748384));
#705=DIRECTION('',(0.,0.,1.));
#706=DIRECTION('',(1.,0.,0.));
#707=AXIS2_PLACEMENT_3D('',#704,#705,#706);
#708=CIRCLE('',#707,1.);
#709=CARTESIAN_POINT('',(18.5312419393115,64.0741376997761,-11.4539814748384));
#710=VERTEX_POINT('',#709);
#711=EDGE_CURVE('E516',#572,#710,#708,.F.);
#712=ORIENTED_EDGE('',*,*,#711,.T.);
#713=EDGE_CURVE('E421',#710,#665,#270,.T.);
#714=ORIENTED_EDGE('',*,*,#713,.T.);
#715=ORIENTED_EDGE('',*,*,#666,.T.);
#716=EDGE_LOOP('',(#703,#712,#714,#715));
#717=FACE_BOUND('',#716,.T.);
#718=ADVANCED_FACE('F879',(#717),#266,.F.);
#719=CARTESIAN_POINT('',(17.5312419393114,65.0741376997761,-0.999999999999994));
#720=DIRECTION('',(0.,0.,1.));
#721=DIRECTION('',(1.,0.,0.));
#722=AXIS2_PLACEMENT_3D('',#719,#720,#721);
#723=PLANE('',#722);
#724=DIRECTION('',(1.,0.,0.));
#725=VECTOR('',#724,1.);
#726=CARTESIAN_POINT('',(17.5312419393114,65.0741376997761,-0.999999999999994));
#727=LINE('',#726,#725);
#728=CARTESIAN_POINT('',(51.7312419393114,65.0741376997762,-0.999999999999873));
#729=VERTEX_POINT('',#728);
#730=EDGE_CURVE('E394',#729,#673,#727,.F.);
#731=ORIENTED_EDGE('',*,*,#730,.T.);
#732=ORIENTED_EDGE('',*,*,#674,.F.);
#733=DIRECTION('',(-1.,0.,0.));
#734=VECTOR('',#733,1.);
#735=CARTESIAN_POINT('',(17.5312419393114,64.0741376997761,-0.999999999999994));
#736=LINE('',#735,#734);
#737=CARTESIAN_POINT('',(51.7312419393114,64.0741376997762,-0.999999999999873));
#738=VERTEX_POINT('',#737);
#739=EDGE_CURVE('E402',#738,#665,#736,.T.);
#740=ORIENTED_EDGE('',*,*,#739,.F.);
#741=DIRECTION('',(0.,-1.,0.));
#742=VECTOR('',#741,1.);
#743=CARTESIAN_POINT('',(51.7312419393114,65.0741376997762,-0.999999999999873));
#744=LINE('',#743,#742);
#745=EDGE_CURVE('E388',#729,#738,#744,.T.);
#746=ORIENTED_EDGE('',*,*,#745,.F.);
#747=EDGE_LOOP('',(#731,#732,#740,#746));
#748=FACE_BOUND('',#747,.T.);
#749=ADVANCED_FACE('F917',(#748),#723,.T.);
#750=CARTESIAN_POINT('',(51.7312419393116,65.0741376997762,-43.7999999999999));
#751=DIRECTION('',(0.,0.,-1.));
#752=DIRECTION('',(-1.,0.,0.));
#753=AXIS2_PLACEMENT_3D('',#750,#751,#752);
#754=PLANE('',#753);
#755=DIRECTION('',(1.,0.,0.));
#756=VECTOR('',#755,1.);
#757=CARTESIAN_POINT('',(17.5312419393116,64.0741376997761,-43.8));
#758=LINE('',#757,#756);
#759=CARTESIAN_POINT('',(51.7312419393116,64.0741376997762,-43.7999999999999));
#760=VERTEX_POINT('',#759);
#761=EDGE_CURVE('E408',#272,#760,#758,.T.);
#762=ORIENTED_EDGE('',*,*,#761,.F.);
#763=ORIENTED_EDGE('',*,*,#646,.T.);
#764=DIRECTION('',(-1.,0.,0.));
#765=VECTOR('',#764,1.);
#766=CARTESIAN_POINT('',(51.7312419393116,65.0741376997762,-43.7999999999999));
#767=LINE('',#766,#765);
#768=CARTESIAN_POINT('',(51.7312419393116,65.0741376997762,-43.7999999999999));
#769=VERTEX_POINT('',#768);
#770=EDGE_CURVE('E400',#248,#769,#767,.F.);
#771=ORIENTED_EDGE('',*,*,#770,.T.);
#772=DIRECTION('',(0.,-1.,0.));
#773=VECTOR('',#772,1.);
#774=CARTESIAN_POINT('',(51.7312419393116,65.0741376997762,-43.7999999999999));
#775=LINE('',#774,#773);
#776=EDGE_CURVE('E391',#769,#760,#775,.T.);
#777=ORIENTED_EDGE('',*,*,#776,.T.);
#778=EDGE_LOOP('',(#762,#763,#771,#777));
#779=FACE_BOUND('',#778,.T.);
#780=ADVANCED_FACE('F907',(#779),#754,.T.);
#781=CARTESIAN_POINT('',(17.5312419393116,65.0741376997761,-43.8));
#782=DIRECTION('',(0.,-1.,0.));
#783=DIRECTION('',(1.,0.,0.));
#784=AXIS2_PLACEMENT_3D('',#781,#782,#783);
#785=PLANE('',#784);
#786=ORIENTED_EDGE('',*,*,#698,.F.);
#787=ORIENTED_EDGE('',*,*,#730,.F.);
#788=DIRECTION('',(0.,0.,-1.));
#789=VECTOR('',#788,1.);
#790=CARTESIAN_POINT('',(51.7312419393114,65.0741376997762,-0.999999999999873));
#791=LINE('',#790,#789);
#792=EDGE_CURVE('E397',#769,#729,#791,.F.);
#793=ORIENTED_EDGE('',*,*,#792,.F.);
#794=ORIENTED_EDGE('',*,*,#770,.F.);
#795=ORIENTED_EDGE('',*,*,#249,.F.);
#796=DIRECTION('',(0.,0.,-1.));
#797=VECTOR('',#796,1.);
#798=CARTESIAN_POINT('',(18.5312419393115,65.0741376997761,-34.2139404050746));
#799=LINE('',#798,#797);
#800=EDGE_CURVE('E342',#693,#240,#799,.T.);
#801=ORIENTED_EDGE('',*,*,#800,.F.);
#802=EDGE_LOOP('',(#786,#787,#793,#794,#795,#801));
#803=FACE_BOUND('',#802,.T.);
#804=ADVANCED_FACE('F897',(#803),#785,.F.);
#805=CARTESIAN_POINT('',(17.5312419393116,64.0741376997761,-43.8));
#806=DIRECTION('',(0.,-1.,0.));
#807=DIRECTION('',(1.,0.,0.));
#808=AXIS2_PLACEMENT_3D('',#805,#806,#807);
#809=PLANE('',#808);
#810=ORIENTED_EDGE('',*,*,#739,.T.);
#811=ORIENTED_EDGE('',*,*,#713,.F.);
#812=EDGE_CURVE('E420',#274,#710,#270,.T.);
#813=ORIENTED_EDGE('',*,*,#812,.F.);
#814=ORIENTED_EDGE('',*,*,#275,.F.);
#815=ORIENTED_EDGE('',*,*,#761,.T.);
#816=DIRECTION('',(0.,0.,1.));
#817=VECTOR('',#816,1.);
#818=CARTESIAN_POINT('',(51.7312419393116,64.0741376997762,-43.7999999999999));
#819=LINE('',#818,#817);
#820=EDGE_CURVE('E405',#760,#738,#819,.T.);
#821=ORIENTED_EDGE('',*,*,#820,.T.);
#822=EDGE_LOOP('',(#810,#811,#813,#814,#815,#821));
#823=FACE_BOUND('',#822,.T.);
#824=ADVANCED_FACE('F888',(#823),#809,.T.);
#825=CARTESIAN_POINT('',(51.7312419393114,65.0741376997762,-0.999999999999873));
#826=DIRECTION('',(1.,0.,0.));
#827=DIRECTION('',(0.,1.,0.));
#828=AXIS2_PLACEMENT_3D('',#825,#826,#827);
#829=PLANE('',#828);
#830=ORIENTED_EDGE('',*,*,#820,.F.);
#831=ORIENTED_EDGE('',*,*,#776,.F.);
#832=ORIENTED_EDGE('',*,*,#792,.T.);
#833=ORIENTED_EDGE('',*,*,#745,.T.);
#834=EDGE_LOOP('',(#830,#831,#832,#833));
#835=FACE_BOUND('',#834,.T.);
#836=ADVANCED_FACE('F855',(#835),#829,.T.);
#837=CARTESIAN_POINT('',(18.5312419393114,41.7710744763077,-11.2878468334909));
#838=DIRECTION('',(0.,0.,1.));
#839=DIRECTION('',(1.,0.,0.));
#840=AXIS2_PLACEMENT_3D('',#837,#838,#839);
#841=PLANE('',#840);
#842=ORIENTED_EDGE('',*,*,#614,.T.);
#843=DIRECTION('',(-1.,0.,0.));
#844=VECTOR('',#843,1.);
#845=CARTESIAN_POINT('',(18.5312419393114,40.4026864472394,-11.2878468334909));
#846=LINE('',#845,#844);
#847=EDGE_CURVE('E365',#607,#157,#846,.T.);
#848=ORIENTED_EDGE('',*,*,#847,.T.);
#849=ORIENTED_EDGE('',*,*,#158,.T.);
#850=ORIENTED_EDGE('',*,*,#94,.F.);
#851=EDGE_LOOP('',(#842,#848,#849,#850));
#852=FACE_BOUND('',#851,.T.);
#853=ADVANCED_FACE('F540',(#852),#841,.F.);
#854=CARTESIAN_POINT('',(18.5312419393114,40.4026864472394,-11.2878468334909));
#855=DIRECTION('',(0.,-1.,0.));
#856=DIRECTION('',(0.,0.,-1.));
#857=AXIS2_PLACEMENT_3D('',#854,#855,#856);
#858=PLANE('',#857);
#859=ORIENTED_EDGE('',*,*,#608,.T.);
#860=DIRECTION('',(-1.,0.,0.));
#861=VECTOR('',#860,1.);
#862=CARTESIAN_POINT('',(18.5312419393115,40.4026864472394,-16.9317383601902));
#863=LINE('',#862,#861);
#864=EDGE_CURVE('E367',#599,#165,#863,.T.);
#865=ORIENTED_EDGE('',*,*,#864,.T.);
#866=ORIENTED_EDGE('',*,*,#166,.T.);
#867=ORIENTED_EDGE('',*,*,#847,.F.);
#868=EDGE_LOOP('',(#859,#865,#866,#867));
#869=FACE_BOUND('',#868,.T.);
#870=ADVANCED_FACE('F550',(#869),#858,.F.);
#871=CARTESIAN_POINT('',(18.5312419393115,40.4026864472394,-16.9317383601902));
#872=DIRECTION('',(0.,-0.62404437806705,-0.781388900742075));
#873=DIRECTION('',(0.,0.781388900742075,-0.62404437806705));
#874=AXIS2_PLACEMENT_3D('',#871,#872,#873);
#875=PLANE('',#874);
#876=ORIENTED_EDGE('',*,*,#600,.T.);
#877=DIRECTION('',(-1.,0.,0.));
#878=VECTOR('',#877,1.);
#879=CARTESIAN_POINT('',(18.5312419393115,62.0423667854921,-34.2139404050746));
#880=LINE('',#879,#878);
#881=EDGE_CURVE('E369',#591,#173,#880,.T.);
#882=ORIENTED_EDGE('',*,*,#881,.T.);
#883=ORIENTED_EDGE('',*,*,#174,.T.);
#884=ORIENTED_EDGE('',*,*,#864,.F.);
#885=EDGE_LOOP('',(#876,#882,#883,#884));
#886=FACE_BOUND('',#885,.T.);
#887=ADVANCED_FACE('F552',(#886),#875,.F.);
#888=CARTESIAN_POINT('',(18.5312419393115,62.0423667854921,-34.2139404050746));
#889=DIRECTION('',(0.,0.,-1.));
#890=DIRECTION('',(-1.,0.,0.));
#891=AXIS2_PLACEMENT_3D('',#888,#889,#890);
#892=PLANE('',#891);
#893=ORIENTED_EDGE('',*,*,#241,.T.);
#894=ORIENTED_EDGE('',*,*,#182,.T.);
#895=ORIENTED_EDGE('',*,*,#881,.F.);
#896=ORIENTED_EDGE('',*,*,#592,.T.);
#897=ORIENTED_EDGE('',*,*,#284,.F.);
#898=DIRECTION('',(0.,-1.,0.));
#899=VECTOR('',#898,1.);
#900=CARTESIAN_POINT('',(18.5312419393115,62.0423667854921,-34.2139404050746));
#901=LINE('',#900,#899);
#902=EDGE_CURVE('E345',#240,#274,#901,.T.);
#903=ORIENTED_EDGE('',*,*,#902,.F.);
#904=EDGE_LOOP('',(#893,#894,#895,#896,#897,#903));
#905=FACE_BOUND('',#904,.T.);
#906=ADVANCED_FACE('F821',(#905),#892,.F.);
#907=CARTESIAN_POINT('',(18.5312419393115,62.411644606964,-11.4539814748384));
#908=DIRECTION('',(0.,0.,1.));
#909=DIRECTION('',(1.,0.,0.));
#910=AXIS2_PLACEMENT_3D('',#907,#908,#909);
#911=PLANE('',#910);
#912=ORIENTED_EDGE('',*,*,#694,.T.);
#913=DIRECTION('',(0.,1.,0.));
#914=VECTOR('',#913,1.);
#915=CARTESIAN_POINT('',(18.5312419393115,62.411644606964,-11.4539814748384));
#916=LINE('',#915,#914);
#917=EDGE_CURVE('E340',#710,#693,#916,.T.);
#918=ORIENTED_EDGE('',*,*,#917,.F.);
#919=ORIENTED_EDGE('',*,*,#711,.F.);
#920=ORIENTED_EDGE('',*,*,#573,.T.);
#921=ORIENTED_EDGE('',*,*,#134,.T.);
#922=ORIENTED_EDGE('',*,*,#224,.T.);
#923=EDGE_LOOP('',(#912,#918,#919,#920,#921,#922));
#924=FACE_BOUND('',#923,.T.);
#925=ADVANCED_FACE('F580',(#924),#911,.F.);
#926=CARTESIAN_POINT('',(18.5312419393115,62.411644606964,-11.4539814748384));
#927=DIRECTION('',(-1.,0.,0.));
#928=DIRECTION('',(0.,0.,1.));
#929=AXIS2_PLACEMENT_3D('',#926,#927,#928);
#930=PLANE('',#929);
#931=ORIENTED_EDGE('',*,*,#917,.T.);
#932=ORIENTED_EDGE('',*,*,#800,.T.);
#933=ORIENTED_EDGE('',*,*,#902,.T.);
#934=ORIENTED_EDGE('',*,*,#812,.T.);
#935=EDGE_LOOP('',(#931,#932,#933,#934));
#936=FACE_BOUND('',#935,.T.);
#937=ADVANCED_FACE('F666',(#936),#930,.T.);
#938=CARTESIAN_POINT('',(18.5312419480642,62.411644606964,-12.5039962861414));
#939=DIRECTION('',(0.,-1.,0.));
#940=DIRECTION('',(0.,0.,-1.));
#941=AXIS2_PLACEMENT_3D('',#938,#939,#940);
#942=PLANE('',#941);
#943=DIRECTION('',(0.,0.,-1.));
#944=VECTOR('',#943,1.);
#945=CARTESIAN_POINT('',(18.5312419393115,62.411644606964,-12.5039962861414));
#946=LINE('',#945,#944);
#947=CARTESIAN_POINT('',(18.5312419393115,62.411644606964,-13.5039962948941));
#948=VERTEX_POINT('',#947);
#949=CARTESIAN_POINT('',(18.5312419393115,62.411644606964,-14.5039962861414));
#950=VERTEX_POINT('',#949);
#951=EDGE_CURVE('E295',#948,#950,#946,.T.);
#952=ORIENTED_EDGE('',*,*,#951,.T.);
#953=CARTESIAN_POINT('',(18.5312419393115,62.411644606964,-12.5039962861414));
#954=DIRECTION('',(0.,1.,0.));
#955=DIRECTION('',(0.,0.,1.));
#956=AXIS2_PLACEMENT_3D('',#953,#954,#955);
#957=CIRCLE('',#956,2.00000000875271);
#958=EDGE_CURVE('E299',#950,#119,#957,.T.);
#959=ORIENTED_EDGE('',*,*,#958,.T.);
#960=ORIENTED_EDGE('',*,*,#120,.F.);
#961=CARTESIAN_POINT('',(18.5312419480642,62.411644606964,-12.5039962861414));
#962=DIRECTION('',(0.,1.,0.));
#963=DIRECTION('',(0.,0.,-1.));
#964=AXIS2_PLACEMENT_3D('',#961,#962,#963);
#965=CIRCLE('',#964,1.00000001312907);
#966=EDGE_CURVE('E329',#948,#111,#965,.T.);
#967=ORIENTED_EDGE('',*,*,#966,.F.);
#968=EDGE_LOOP('',(#952,#959,#960,#967));
#969=FACE_BOUND('',#968,.T.);
#970=ADVANCED_FACE('F664',(#969),#942,.F.);
#971=CARTESIAN_POINT('',(18.5312419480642,41.7710744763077,-12.5039962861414));
#972=DIRECTION('',(0.,1.,0.));
#973=DIRECTION('',(0.,0.,1.));
#974=AXIS2_PLACEMENT_3D('',#971,#972,#973);
#975=PLANE('',#974);
#976=CARTESIAN_POINT('',(18.5312419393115,41.7710744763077,-12.5039962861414));
#977=DIRECTION('',(0.,1.,0.));
#978=DIRECTION('',(0.,0.,1.));
#979=AXIS2_PLACEMENT_3D('',#976,#977,#978);
#980=CIRCLE('',#979,2.00000000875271);
#981=CARTESIAN_POINT('',(18.5312419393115,41.7710744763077,-14.5039962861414));
#982=VERTEX_POINT('',#981);
#983=EDGE_CURVE('E333',#71,#982,#980,.F.);
#984=ORIENTED_EDGE('',*,*,#983,.T.);
#985=DIRECTION('',(0.,0.,1.));
#986=VECTOR('',#985,1.);
#987=CARTESIAN_POINT('',(18.5312419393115,41.7710744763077,-12.5039962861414));
#988=LINE('',#987,#986);
#989=CARTESIAN_POINT('',(18.5312419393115,41.7710744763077,-13.5039962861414));
#990=VERTEX_POINT('',#989);
#991=EDGE_CURVE('E321',#982,#990,#988,.T.);
#992=ORIENTED_EDGE('',*,*,#991,.T.);
#993=CARTESIAN_POINT('',(18.5312419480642,41.7710744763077,-12.5039962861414));
#994=DIRECTION('',(0.,-1.,0.));
#995=DIRECTION('',(0.,0.,1.));
#996=AXIS2_PLACEMENT_3D('',#993,#994,#995);
#997=CIRCLE('',#996,1.00000001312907);
#998=EDGE_CURVE('E332',#79,#990,#997,.T.);
#999=ORIENTED_EDGE('',*,*,#998,.F.);
#1000=ORIENTED_EDGE('',*,*,#80,.F.);
#1001=EDGE_LOOP('',(#984,#992,#999,#1000));
#1002=FACE_BOUND('',#1001,.T.);
#1003=ADVANCED_FACE('F568',(#1002),#975,.F.);
#1004=CARTESIAN_POINT('',(18.5312419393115,31.2926868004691,-12.5039962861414));
#1005=DIRECTION('',(0.,1.,0.));
#1006=DIRECTION('',(0.,0.,1.));
#1007=AXIS2_PLACEMENT_3D('',#1004,#1005,#1006);
#1008=CYLINDRICAL_SURFACE('',#1007,1.00000000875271);
#1009=ORIENTED_EDGE('',*,*,#564,.T.);
#1010=ORIENTED_EDGE('',*,*,#998,.T.);
#1011=DIRECTION('',(0.,-1.,0.));
#1012=VECTOR('',#1011,1.);
#1013=CARTESIAN_POINT('',(18.5312419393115,0.,-13.5039962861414));
#1014=LINE('',#1013,#1012);
#1015=EDGE_CURVE('E311',#948,#990,#1014,.T.);
#1016=ORIENTED_EDGE('',*,*,#1015,.F.);
#1017=ORIENTED_EDGE('',*,*,#966,.T.);
#1018=EDGE_LOOP('',(#1009,#1010,#1016,#1017));
#1019=FACE_BOUND('',#1018,.T.);
#1020=ADVANCED_FACE('F573',(#1019),#1008,.F.);
#1021=CARTESIAN_POINT('',(18.5312419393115,31.2926868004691,-12.5039962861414));
#1022=DIRECTION('',(0.,1.,0.));
#1023=DIRECTION('',(0.,0.,1.));
#1024=AXIS2_PLACEMENT_3D('',#1021,#1022,#1023);
#1025=CYLINDRICAL_SURFACE('',#1024,2.00000000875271);
#1026=ORIENTED_EDGE('',*,*,#149,.F.);
#1027=ORIENTED_EDGE('',*,*,#958,.F.);
#1028=DIRECTION('',(0.,-1.,0.));
#1029=VECTOR('',#1028,1.);
#1030=CARTESIAN_POINT('',(18.5312419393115,0.,-14.5039962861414));
#1031=LINE('',#1030,#1029);
#1032=EDGE_CURVE('E324',#950,#982,#1031,.T.);
#1033=ORIENTED_EDGE('',*,*,#1032,.T.);
#1034=ORIENTED_EDGE('',*,*,#983,.F.);
#1035=EDGE_LOOP('',(#1026,#1027,#1033,#1034));
#1036=FACE_BOUND('',#1035,.T.);
#1037=ADVANCED_FACE('F565',(#1036),#1025,.T.);
#1038=CARTESIAN_POINT('',(36.7177895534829,62.411644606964,-12.5039962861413));
#1039=DIRECTION('',(-0.781388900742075,0.62404437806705,0.));
#1040=DIRECTION('',(-0.62404437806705,-0.781388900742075,0.));
#1041=AXIS2_PLACEMENT_3D('',#1038,#1039,#1040);
#1042=PLANE('',#1041);
#1043=DIRECTION('',(-0.62404437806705,-0.781388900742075,0.));
#1044=VECTOR('',#1043,1.);
#1045=CARTESIAN_POINT('',(-6.58489800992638,8.1907580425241,-13.5039962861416));
#1046=LINE('',#1045,#1044);
#1047=CARTESIAN_POINT('',(20.233511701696,41.7710744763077,-13.5039962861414));
#1048=VERTEX_POINT('',#1047);
#1049=EDGE_CURVE('E319',#47,#1048,#1046,.T.);
#1050=ORIENTED_EDGE('',*,*,#1049,.T.);
#1051=DIRECTION('',(0.,0.,-1.));
#1052=VECTOR('',#1051,1.);
#1053=CARTESIAN_POINT('',(20.233511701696,41.7710744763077,-12.5039962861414));
#1054=LINE('',#1053,#1052);
#1055=CARTESIAN_POINT('',(20.233511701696,41.7710744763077,-14.5039962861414));
#1056=VERTEX_POINT('',#1055);
#1057=EDGE_CURVE('E316',#1048,#1056,#1054,.T.);
#1058=ORIENTED_EDGE('',*,*,#1057,.T.);
#1059=DIRECTION('',(0.62404437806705,0.781388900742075,0.));
#1060=VECTOR('',#1059,1.);
#1061=CARTESIAN_POINT('',(36.717789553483,62.411644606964,-14.5039962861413));
#1062=LINE('',#1061,#1060);
#1063=EDGE_CURVE('E313',#1056,#29,#1062,.T.);
#1064=ORIENTED_EDGE('',*,*,#1063,.T.);
#1065=ORIENTED_EDGE('',*,*,#54,.F.);
#1066=EDGE_LOOP('',(#1050,#1058,#1064,#1065));
#1067=FACE_BOUND('',#1066,.T.);
#1068=ADVANCED_FACE('F660',(#1067),#1042,.F.);
#1069=CARTESIAN_POINT('',(3.67105116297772,0.,-13.5039962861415));
#1070=DIRECTION('',(0.,0.,1.));
#1071=DIRECTION('',(1.,0.,0.));
#1072=AXIS2_PLACEMENT_3D('',#1069,#1070,#1071);
#1073=PLANE('',#1072);
#1074=CARTESIAN_POINT('',(21.9404161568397,62.411644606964,-13.5039962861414));
#1075=VERTEX_POINT('',#1074);
#1076=EDGE_CURVE('E303',#948,#1075,#45,.T.);
#1077=ORIENTED_EDGE('',*,*,#1076,.F.);
#1078=ORIENTED_EDGE('',*,*,#1015,.T.);
#1079=DIRECTION('',(-1.,0.,0.));
#1080=VECTOR('',#1079,1.);
#1081=CARTESIAN_POINT('',(3.67105116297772,41.7710744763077,-13.5039962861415));
#1082=LINE('',#1081,#1080);
#1083=EDGE_CURVE('E306',#1048,#990,#1082,.T.);
#1084=ORIENTED_EDGE('',*,*,#1083,.F.);
#1085=ORIENTED_EDGE('',*,*,#1049,.F.);
#1086=ORIENTED_EDGE('',*,*,#48,.F.);
#1087=DIRECTION('',(0.,-1.,0.));
#1088=VECTOR('',#1087,1.);
#1089=CARTESIAN_POINT('',(34.0135990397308,62.411644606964,-13.5039962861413));
#1090=LINE('',#1089,#1088);
#1091=CARTESIAN_POINT('',(34.0135990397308,64.0641376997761,-13.5039962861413));
#1092=VERTEX_POINT('',#1091);
#1093=EDGE_CURVE('E280',#1092,#39,#1090,.T.);
#1094=ORIENTED_EDGE('',*,*,#1093,.F.);
#1095=DIRECTION('',(1.,0.,0.));
#1096=VECTOR('',#1095,1.);
#1097=CARTESIAN_POINT('',(34.0135990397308,64.0641376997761,-13.5039962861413));
#1098=LINE('',#1097,#1096);
#1099=CARTESIAN_POINT('',(21.9404161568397,64.0641376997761,-13.5039962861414));
#1100=VERTEX_POINT('',#1099);
#1101=EDGE_CURVE('E264',#1100,#1092,#1098,.T.);
#1102=ORIENTED_EDGE('',*,*,#1101,.F.);
#1103=DIRECTION('',(0.,1.,0.));
#1104=VECTOR('',#1103,1.);
#1105=CARTESIAN_POINT('',(21.9404161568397,62.411644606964,-13.5039962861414));
#1106=LINE('',#1105,#1104);
#1107=EDGE_CURVE('E275',#1075,#1100,#1106,.T.);
#1108=ORIENTED_EDGE('',*,*,#1107,.F.);
#1109=EDGE_LOOP('',(#1077,#1078,#1084,#1085,#1086,#1094,#1102,#1108));
#1110=FACE_BOUND('',#1109,.T.);
#1111=ADVANCED_FACE('F283',(#1110),#1073,.T.);
#1112=CARTESIAN_POINT('',(20.233511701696,41.7710744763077,-12.5039962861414));
#1113=DIRECTION('',(0.,1.,0.));
#1114=DIRECTION('',(-1.,0.,0.));
#1115=AXIS2_PLACEMENT_3D('',#1112,#1113,#1114);
#1116=PLANE('',#1115);
#1117=ORIENTED_EDGE('',*,*,#991,.F.);
#1118=DIRECTION('',(1.,0.,0.));
#1119=VECTOR('',#1118,1.);
#1120=CARTESIAN_POINT('',(20.233511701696,41.7710744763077,-14.5039962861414));
#1121=LINE('',#1120,#1119);
#1122=EDGE_CURVE('E309',#982,#1056,#1121,.T.);
#1123=ORIENTED_EDGE('',*,*,#1122,.T.);
#1124=ORIENTED_EDGE('',*,*,#1057,.F.);
#1125=ORIENTED_EDGE('',*,*,#1083,.T.);
#1126=EDGE_LOOP('',(#1117,#1123,#1124,#1125));
#1127=FACE_BOUND('',#1126,.T.);
#1128=ADVANCED_FACE('F652',(#1127),#1116,.F.);
#1129=CARTESIAN_POINT('',(3.67105116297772,0.,-14.5039962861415));
#1130=DIRECTION('',(0.,0.,1.));
#1131=DIRECTION('',(1.,0.,0.));
#1132=AXIS2_PLACEMENT_3D('',#1129,#1130,#1131);
#1133=PLANE('',#1132);
#1134=ORIENTED_EDGE('',*,*,#1032,.F.);
#1135=CARTESIAN_POINT('',(21.9404161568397,62.411644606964,-14.5039962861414));
#1136=VERTEX_POINT('',#1135);
#1137=EDGE_CURVE('E300',#1136,#950,#27,.T.);
#1138=ORIENTED_EDGE('',*,*,#1137,.F.);
#1139=DIRECTION('',(0.,1.,0.));
#1140=VECTOR('',#1139,1.);
#1141=CARTESIAN_POINT('',(21.9404161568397,62.411644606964,-14.5039962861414));
#1142=LINE('',#1141,#1140);
#1143=CARTESIAN_POINT('',(21.9404161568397,64.0641376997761,-14.5039962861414));
#1144=VERTEX_POINT('',#1143);
#1145=EDGE_CURVE('E292',#1136,#1144,#1142,.T.);
#1146=ORIENTED_EDGE('',*,*,#1145,.T.);
#1147=DIRECTION('',(1.,0.,0.));
#1148=VECTOR('',#1147,1.);
#1149=CARTESIAN_POINT('',(34.0135990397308,64.0641376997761,-14.5039962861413));
#1150=LINE('',#1149,#1148);
#1151=CARTESIAN_POINT('',(34.0135990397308,64.0641376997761,-14.5039962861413));
#1152=VERTEX_POINT('',#1151);
#1153=EDGE_CURVE('E266',#1144,#1152,#1150,.T.);
#1154=ORIENTED_EDGE('',*,*,#1153,.T.);
#1155=DIRECTION('',(0.,-1.,0.));
#1156=VECTOR('',#1155,1.);
#1157=CARTESIAN_POINT('',(34.0135990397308,62.411644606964,-14.5039962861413));
#1158=LINE('',#1157,#1156);
#1159=EDGE_CURVE('E289',#1152,#31,#1158,.T.);
#1160=ORIENTED_EDGE('',*,*,#1159,.T.);
#1161=ORIENTED_EDGE('',*,*,#32,.F.);
#1162=ORIENTED_EDGE('',*,*,#1063,.F.);
#1163=ORIENTED_EDGE('',*,*,#1122,.F.);
#1164=EDGE_LOOP('',(#1134,#1138,#1146,#1154,#1160,#1161,#1162,#1163));
#1165=FACE_BOUND('',#1164,.T.);
#1166=ADVANCED_FACE('F644',(#1165),#1133,.F.);
#1167=ORIENTED_EDGE('',*,*,#1076,.T.);
#1168=DIRECTION('',(0.,0.,-1.));
#1169=VECTOR('',#1168,1.);
#1170=CARTESIAN_POINT('',(21.9404161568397,62.411644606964,-13.5039962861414));
#1171=LINE('',#1170,#1169);
#1172=EDGE_CURVE('E271',#1075,#1136,#1171,.T.);
#1173=ORIENTED_EDGE('',*,*,#1172,.T.);
#1174=ORIENTED_EDGE('',*,*,#1137,.T.);
#1175=ORIENTED_EDGE('',*,*,#951,.F.);
#1176=EDGE_LOOP('',(#1167,#1173,#1174,#1175));
#1177=FACE_BOUND('',#1176,.T.);
#1178=ADVANCED_FACE('F635',(#1177),#23,.F.);
#1179=CARTESIAN_POINT('',(34.0135990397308,62.411644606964,-13.5039962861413));
#1180=DIRECTION('',(1.,0.,0.));
#1181=DIRECTION('',(0.,0.,-1.));
#1182=AXIS2_PLACEMENT_3D('',#1179,#1180,#1181);
#1183=PLANE('',#1182);
#1184=ORIENTED_EDGE('',*,*,#1159,.F.);
#1185=DIRECTION('',(0.,0.,-1.));
#1186=VECTOR('',#1185,1.);
#1187=CARTESIAN_POINT('',(34.0135990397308,64.0641376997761,-13.5039962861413));
#1188=LINE('',#1187,#1186);
#1189=EDGE_CURVE('E270',#1092,#1152,#1188,.T.);
#1190=ORIENTED_EDGE('',*,*,#1189,.F.);
#1191=ORIENTED_EDGE('',*,*,#1093,.T.);
#1192=ORIENTED_EDGE('',*,*,#40,.T.);
#1193=EDGE_LOOP('',(#1184,#1190,#1191,#1192));
#1194=FACE_BOUND('',#1193,.T.);
#1195=ADVANCED_FACE('F643',(#1194),#1183,.T.);
#1196=CARTESIAN_POINT('',(34.0135990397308,64.0641376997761,-13.5039962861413));
#1197=DIRECTION('',(0.,1.,0.));
#1198=DIRECTION('',(0.,0.,1.));
#1199=AXIS2_PLACEMENT_3D('',#1196,#1197,#1198);
#1200=PLANE('',#1199);
#1201=ORIENTED_EDGE('',*,*,#1153,.F.);
#1202=DIRECTION('',(0.,0.,-1.));
#1203=VECTOR('',#1202,1.);
#1204=CARTESIAN_POINT('',(21.9404161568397,64.0641376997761,-13.5039962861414));
#1205=LINE('',#1204,#1203);
#1206=EDGE_CURVE('E260',#1100,#1144,#1205,.T.);
#1207=ORIENTED_EDGE('',*,*,#1206,.F.);
#1208=ORIENTED_EDGE('',*,*,#1101,.T.);
#1209=ORIENTED_EDGE('',*,*,#1189,.T.);
#1210=EDGE_LOOP('',(#1201,#1207,#1208,#1209));
#1211=FACE_BOUND('',#1210,.T.);
#1212=ADVANCED_FACE('F262',(#1211),#1200,.T.);
#1213=CARTESIAN_POINT('',(21.9404161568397,62.411644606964,-13.5039962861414));
#1214=DIRECTION('',(-1.,0.,0.));
#1215=DIRECTION('',(0.,0.,1.));
#1216=AXIS2_PLACEMENT_3D('',#1213,#1214,#1215);
#1217=PLANE('',#1216);
#1218=ORIENTED_EDGE('',*,*,#1145,.F.);
#1219=ORIENTED_EDGE('',*,*,#1172,.F.);
#1220=ORIENTED_EDGE('',*,*,#1107,.T.);
#1221=ORIENTED_EDGE('',*,*,#1206,.T.);
#1222=EDGE_LOOP('',(#1218,#1219,#1220,#1221));
#1223=FACE_BOUND('',#1222,.T.);
#1224=ADVANCED_FACE('F276',(#1223),#1217,.T.);
#1225=CLOSED_SHELL('',(#58,#98,#138,#228,#261,#303,#343,#383,#405,#427,#439,#470,#501,#518,#530,
#554,#619,#636,#653,#686,#702,#718,#749,#780,#804,#824,#836,#853,#870,#887,#906,#925,#937,#970,
#1003,#1020,#1037,#1068,#1111,#1128,#1166,#1178,#1195,#1212,#1224));
#1226=MANIFOLD_SOLID_BREP('B2',#1225);
#1227=ADVANCED_BREP_SHAPE_REPRESENTATION('',(#18,#1226),#14);
#1228=SHAPE_DEFINITION_REPRESENTATION(#9,#1227);
ENDSEC;
END-ISO-10303-21;
